VERSION 5.7 ;
  NOWIREEXTENSIONATPIN ON ;
  DIVIDERCHAR "/" ;
  BUSBITCHARS "[]" ;
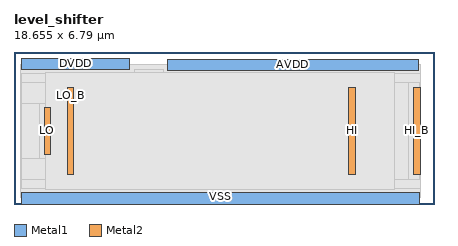
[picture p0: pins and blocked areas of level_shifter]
MACRO level_shifter
  CLASS BLOCK ;
  FOREIGN level_shifter ;
  ORIGIN 0.000 -0.040 ;
  SIZE 18.655 BY 6.790 ;
  PIN AVDD
    ANTENNADIFFAREA 11.408000 ;
    PORT
      LAYER Metal1 ;
        RECT 6.815 5.980 17.965 6.480 ;
    END
  END AVDD
  PIN LO_B
    ANTENNAGATEAREA 0.631200 ;
    ANTENNADIFFAREA 0.591600 ;
    PORT
      LAYER Metal2 ;
        RECT 2.360 1.335 2.660 5.225 ;
    END
  END LO_B
  PIN DVDD
    ANTENNADIFFAREA 5.511600 ;
    PORT
      LAYER Metal1 ;
        RECT 0.350 6.015 5.150 6.515 ;
    END
  END DVDD
  PIN LO
    ANTENNAGATEAREA 0.226200 ;
    PORT
      LAYER Metal2 ;
        RECT 1.335 2.255 1.635 4.315 ;
    END
  END LO
  PIN HI
    ANTENNAGATEAREA 0.725000 ;
    ANTENNADIFFAREA 0.578000 ;
    PORT
      LAYER Metal2 ;
        RECT 14.855 1.350 15.155 5.220 ;
    END
  END HI
  PIN VSS
    USE GROUND ;
    PORT
      LAYER Metal1 ;
        RECT 0.350 0.040 17.990 0.540 ;
    END
  END VSS
  PIN HI_B
    ANTENNADIFFAREA 0.578000 ;
    PORT
      LAYER Metal2 ;
        RECT 17.735 1.350 18.035 5.220 ;
    END
  END HI_B
  OBS
      LAYER GatPoly ;
        RECT 0.310 0.310 18.060 6.245 ;
      LAYER Metal1 ;
        RECT 5.330 5.835 6.635 6.015 ;
        RECT 0.350 5.800 6.635 5.835 ;
        RECT 0.350 0.720 17.990 5.800 ;
      LAYER Metal2 ;
        RECT 0.350 5.435 18.060 5.830 ;
        RECT 0.350 4.525 2.150 5.435 ;
        RECT 0.350 2.045 1.125 4.525 ;
        RECT 1.845 2.045 2.150 4.525 ;
        RECT 0.350 1.125 2.150 2.045 ;
        RECT 2.870 5.430 18.060 5.435 ;
        RECT 2.870 1.140 14.645 5.430 ;
        RECT 15.365 1.140 17.525 5.430 ;
        RECT 2.870 1.125 18.060 1.140 ;
        RECT 0.350 0.725 18.060 1.125 ;
      LAYER Metal3 ;
        RECT 1.385 0.685 16.880 5.870 ;
  END
END level_shifter
END LIBRARY

